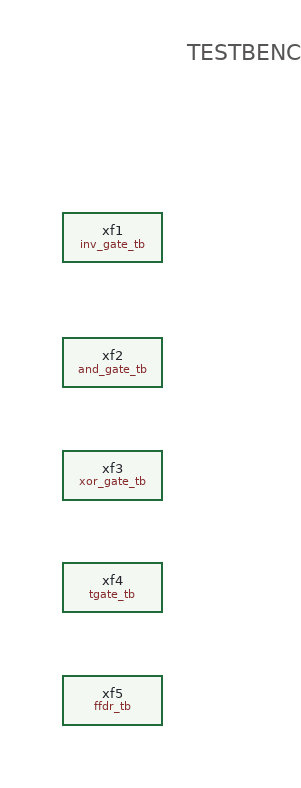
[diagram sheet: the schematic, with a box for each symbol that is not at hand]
v {xschem version=3.4.4 file_version=1.2

* Copyright 2022 GlobalFoundries PDK Authors
*
* Licensed under the Apache License, Version 2.0 (the "License");
* you may not use this file except in compliance with the License.
* You may obtain a copy of the License at
*
*     https://www.apache.org/licenses/LICENSE-2.0
*
* Unless required by applicable law or agreed to in writing, software
* distributed under the License is distributed on an "AS IS" BASIS,
* WITHOUT WARRANTIES OR CONDITIONS OF ANY KIND, either express or implied.
* See the License for the specific language governing permissions and
* limitations under the License.

}
G {}
K {}
V {}
S {}
E {}
T {TESTBENCH} 110 -830 0 0 0.8 0.8 {}
C {devices/title.sym} 160 -30 0 0 {name=l5 author="Jesus Avila"}
C {inv_gate_tb.sym} 50 -670 0 0 {name=xf1}
C {and_gate_tb.sym} 50 -570 0 0 {name=xf2}
C {xor_gate_tb.sym} 50 -480 0 0 {name=xf3}
C {tgate_tb.sym} 50 -390 0 0 {name=xf4}
C {ffdr_tb.sym} 50 -300 0 0 {name=xf5}
